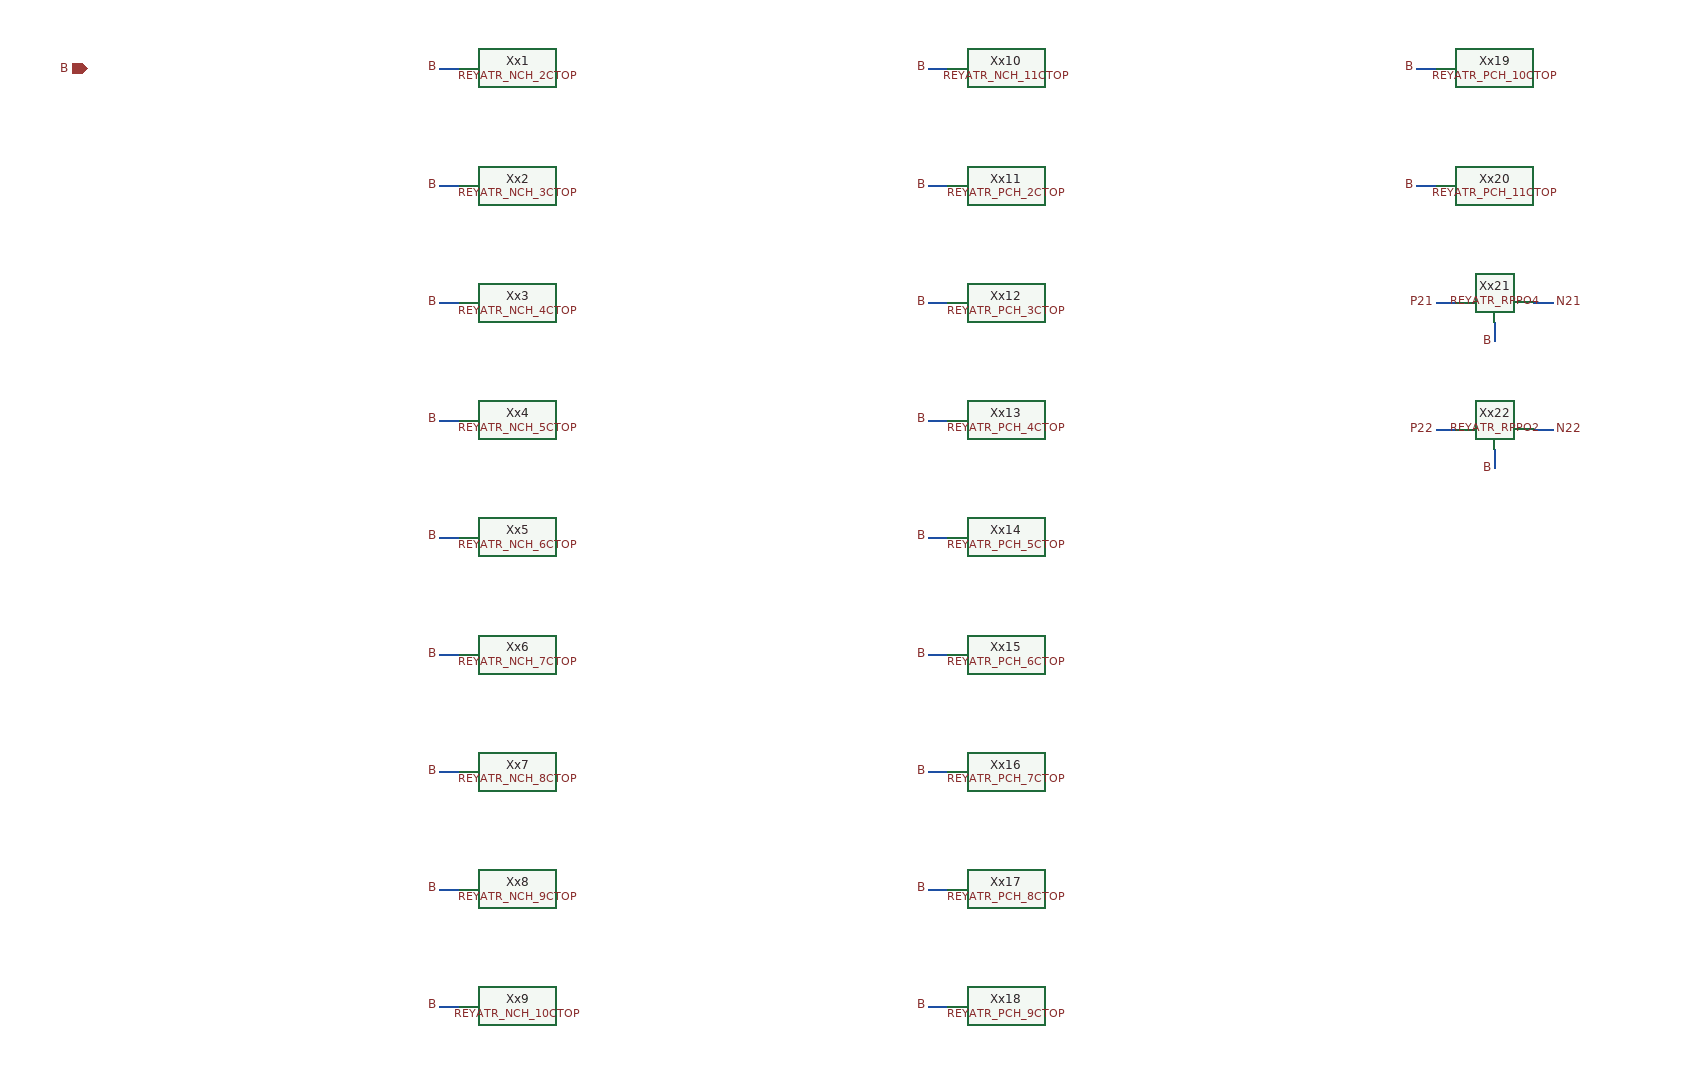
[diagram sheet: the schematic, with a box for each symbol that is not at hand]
v {xschem version=3.0.0 file_version=1.2 }
G {}
K {}
V {}
S {}
E {}
C {devices/iopin.sym} 0 0 0 0 {name=p0 lab=B}
C {LELO_TEMP_SKY130A/REYATR_NCH_2CTOP.sym} 400 0 0 0 {name=Xx1}
N 360.0 0.0 380.0 0.0 {lab=B}
C {devices/lab_pin.sym} 360.0 0.0 0 0 {name=l0 sig_type=std_logic lab=B }
C {LELO_TEMP_SKY130A/REYATR_NCH_3CTOP.sym} 400 120.0 0 0 {name=Xx2}
N 360.0 120.0 380.0 120.0 {lab=B}
C {devices/lab_pin.sym} 360.0 120.0 0 0 {name=l1 sig_type=std_logic lab=B }
C {LELO_TEMP_SKY130A/REYATR_NCH_4CTOP.sym} 400 240.0 0 0 {name=Xx3}
N 360.0 240.0 380.0 240.0 {lab=B}
C {devices/lab_pin.sym} 360.0 240.0 0 0 {name=l2 sig_type=std_logic lab=B }
C {LELO_TEMP_SKY130A/REYATR_NCH_5CTOP.sym} 400 360.0 0 0 {name=Xx4}
N 360.0 360.0 380.0 360.0 {lab=B}
C {devices/lab_pin.sym} 360.0 360.0 0 0 {name=l3 sig_type=std_logic lab=B }
C {LELO_TEMP_SKY130A/REYATR_NCH_6CTOP.sym} 400 480.0 0 0 {name=Xx5}
N 360.0 480.0 380.0 480.0 {lab=B}
C {devices/lab_pin.sym} 360.0 480.0 0 0 {name=l4 sig_type=std_logic lab=B }
C {LELO_TEMP_SKY130A/REYATR_NCH_7CTOP.sym} 400 600.0 0 0 {name=Xx6}
N 360.0 600.0 380.0 600.0 {lab=B}
C {devices/lab_pin.sym} 360.0 600.0 0 0 {name=l5 sig_type=std_logic lab=B }
C {LELO_TEMP_SKY130A/REYATR_NCH_8CTOP.sym} 400 720.0 0 0 {name=Xx7}
N 360.0 720.0 380.0 720.0 {lab=B}
C {devices/lab_pin.sym} 360.0 720.0 0 0 {name=l6 sig_type=std_logic lab=B }
C {LELO_TEMP_SKY130A/REYATR_NCH_9CTOP.sym} 400 840.0 0 0 {name=Xx8}
N 360.0 840.0 380.0 840.0 {lab=B}
C {devices/lab_pin.sym} 360.0 840.0 0 0 {name=l7 sig_type=std_logic lab=B }
C {LELO_TEMP_SKY130A/REYATR_NCH_10CTOP.sym} 400 960.0 0 0 {name=Xx9}
N 360.0 960.0 380.0 960.0 {lab=B}
C {devices/lab_pin.sym} 360.0 960.0 0 0 {name=l8 sig_type=std_logic lab=B }
C {LELO_TEMP_SKY130A/REYATR_NCH_11CTOP.sym} 900 0 0 0 {name=Xx10}
N 860.0 0.0 880.0 0.0 {lab=B}
C {devices/lab_pin.sym} 860.0 0.0 0 0 {name=l9 sig_type=std_logic lab=B }
C {LELO_TEMP_SKY130A/REYATR_PCH_2CTOP.sym} 900 120.0 0 0 {name=Xx11}
N 860.0 120.0 880.0 120.0 {lab=B}
C {devices/lab_pin.sym} 860.0 120.0 0 0 {name=l10 sig_type=std_logic lab=B }
C {LELO_TEMP_SKY130A/REYATR_PCH_3CTOP.sym} 900 240.0 0 0 {name=Xx12}
N 860.0 240.0 880.0 240.0 {lab=B}
C {devices/lab_pin.sym} 860.0 240.0 0 0 {name=l11 sig_type=std_logic lab=B }
C {LELO_TEMP_SKY130A/REYATR_PCH_4CTOP.sym} 900 360.0 0 0 {name=Xx13}
N 860.0 360.0 880.0 360.0 {lab=B}
C {devices/lab_pin.sym} 860.0 360.0 0 0 {name=l12 sig_type=std_logic lab=B }
C {LELO_TEMP_SKY130A/REYATR_PCH_5CTOP.sym} 900 480.0 0 0 {name=Xx14}
N 860.0 480.0 880.0 480.0 {lab=B}
C {devices/lab_pin.sym} 860.0 480.0 0 0 {name=l13 sig_type=std_logic lab=B }
C {LELO_TEMP_SKY130A/REYATR_PCH_6CTOP.sym} 900 600.0 0 0 {name=Xx15}
N 860.0 600.0 880.0 600.0 {lab=B}
C {devices/lab_pin.sym} 860.0 600.0 0 0 {name=l14 sig_type=std_logic lab=B }
C {LELO_TEMP_SKY130A/REYATR_PCH_7CTOP.sym} 900 720.0 0 0 {name=Xx16}
N 860.0 720.0 880.0 720.0 {lab=B}
C {devices/lab_pin.sym} 860.0 720.0 0 0 {name=l15 sig_type=std_logic lab=B }
C {LELO_TEMP_SKY130A/REYATR_PCH_8CTOP.sym} 900 840.0 0 0 {name=Xx17}
N 860.0 840.0 880.0 840.0 {lab=B}
C {devices/lab_pin.sym} 860.0 840.0 0 0 {name=l16 sig_type=std_logic lab=B }
C {LELO_TEMP_SKY130A/REYATR_PCH_9CTOP.sym} 900 960.0 0 0 {name=Xx18}
N 860.0 960.0 880.0 960.0 {lab=B}
C {devices/lab_pin.sym} 860.0 960.0 0 0 {name=l17 sig_type=std_logic lab=B }
C {LELO_TEMP_SKY130A/REYATR_PCH_10CTOP.sym} 1400 0 0 0 {name=Xx19}
N 1360.0 0.0 1380.0 0.0 {lab=B}
C {devices/lab_pin.sym} 1360.0 0.0 0 0 {name=l18 sig_type=std_logic lab=B }
C {LELO_TEMP_SKY130A/REYATR_PCH_11CTOP.sym} 1400 120.0 0 0 {name=Xx20}
N 1360.0 120.0 1380.0 120.0 {lab=B}
C {devices/lab_pin.sym} 1360.0 120.0 0 0 {name=l19 sig_type=std_logic lab=B }
C {LELO_TEMP_SKY130A/REYATR_RPPO4.sym} 1400 240.0 0 0 {name=Xx21}
N 1380.0 240.0 1400.0 240.0 {lab=P21}
C {devices/lab_pin.sym} 1380.0 240.0 0 0 {name=l20 sig_type=std_logic lab=P21 }
N 1500.0 240.0 1480.0 240.0 {lab=N21}
C {devices/lab_pin.sym} 1500.0 240.0 2 0 {name=l21 sig_type=std_logic lab=N21 }
N 1440.0 280.0 1440.0 260.0 {lab=B}
C {devices/lab_pin.sym} 1440.0 280.0 1 0 {name=l22 sig_type=std_logic lab=B }
C {LELO_TEMP_SKY130A/REYATR_RPPO2.sym} 1400 370.0 0 0 {name=Xx22}
N 1380.0 370.0 1400.0 370.0 {lab=P22}
C {devices/lab_pin.sym} 1380.0 370.0 0 0 {name=l23 sig_type=std_logic lab=P22 }
N 1500.0 370.0 1480.0 370.0 {lab=N22}
C {devices/lab_pin.sym} 1500.0 370.0 2 0 {name=l24 sig_type=std_logic lab=N22 }
N 1440.0 410.0 1440.0 390.0 {lab=B}
C {devices/lab_pin.sym} 1440.0 410.0 1 0 {name=l25 sig_type=std_logic lab=B }
